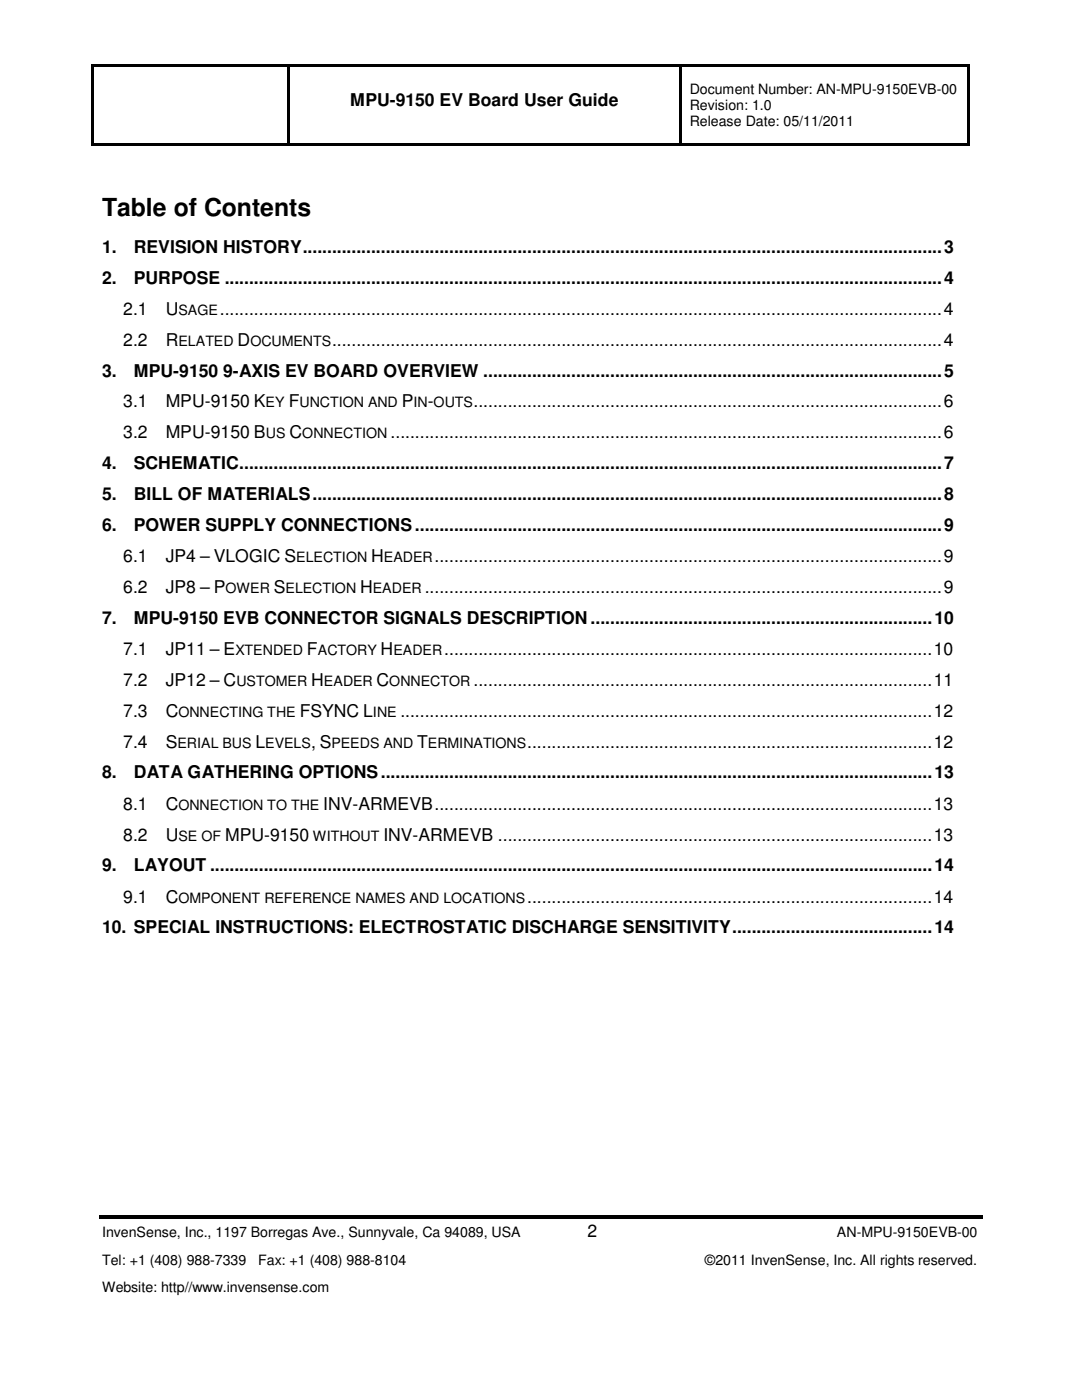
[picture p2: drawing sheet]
<svg xmlns="http://www.w3.org/2000/svg" width="216mm" height="279mm" viewBox="0 0 216 279" stroke-linecap="round" stroke-linejoin="round" font-family="sans-serif">
<defs><g id="words">
<text font-size="5" x="20.4" y="43.1">Table of Contents</text>
<g font-size="3.5">
<text x="69.9" y="21.1">MPU-9150 EV Board User Guide</text>
<text x="20.4" y="50.4">1.</text>
<text x="26.7" y="50.4">REVISION HISTORY ................................................................................................................................... 3</text>
<text x="20.4" y="56.6">2.</text>
<text x="26.7" y="56.6">PURPOSE ................................................................................................................................................... 4</text>
<text x="24.6" y="62.8">2.1</text>
<text x="33.1" y="62.8">U</text>
<text x="43.9" y="62.8">.................................................................................................................................................... 4</text>
<text x="24.6" y="69">2.2</text>
<text x="33.1" y="69">R</text>
<text x="47.4" y="69">D</text>
<text x="66.3" y="69">............................................................................................................................. 4</text>
<text x="20.4" y="75.1">3.</text>
<text x="26.7" y="75.1">MPU-9150 9-AXIS EV BOARD OVERVIEW .............................................................................................. 5</text>
<text x="24.6" y="81.3">3.1</text>
<text x="33.1" y="81.3">MPU-9150 K</text>
<text x="57.6" y="81.3">F</text>
<text x="80.2" y="81.3">P</text>
<text x="85.3" y="81.3">-</text>
<text x="94.5" y="81.3">................................................................................................ 6</text>
<text x="24.6" y="87.5">3.2</text>
<text x="33.1" y="87.5">MPU-9150 B</text>
<text x="57.8" y="87.5">C</text>
<text x="77.9" y="87.5">................................................................................................................. 6</text>
<text x="20.4" y="93.6">4.</text>
<text x="26.7" y="93.6">SCHEMATIC ................................................................................................................................................ 7</text>
<text x="20.4" y="99.8">5.</text>
<text x="26.7" y="99.8">BILL OF MATERIALS ................................................................................................................................. 8</text>
<text x="20.4" y="106">6.</text>
<text x="26.7" y="106">POWER SUPPLY CONNECTIONS ............................................................................................................ 9</text>
<text x="24.6" y="112.2">6.1</text>
<text x="33.1" y="112.2">JP4 – VLOGIC S</text>
<text x="74" y="112.2">H</text>
<text x="86.7" y="112.2">........................................................................................................ 9</text>
<text x="24.6" y="118.4">6.2</text>
<text x="33.1" y="118.4">JP8 – P</text>
<text x="54.7" y="118.4">S</text>
<text x="71.9" y="118.4">H</text>
<text x="84.8" y="118.4">.......................................................................................................... 9</text>
<text x="20.4" y="124.5">7.</text>
<text x="26.7" y="124.5">MPU-9150 EVB CONNECTOR SIGNALS DESCRIPTION ...................................................................... 10</text>
<text x="24.6" y="130.7">7.1</text>
<text x="33.1" y="130.7">JP11 – E</text>
<text x="61.3" y="130.7">F</text>
<text x="75.9" y="130.7">H</text>
<text x="88.6" y="130.7">....................................................................................................10</text>
<text x="24.6" y="136.9">7.2</text>
<text x="33.1" y="136.9">JP12 – C</text>
<text x="62.1" y="136.9">H</text>
<text x="75.1" y="136.9">C</text>
<text x="94.5" y="136.9">.............................................................................................. 11</text>
<text x="24.6" y="143.1">7.3</text>
<text x="33.1" y="143.1">C</text>
<text x="59.8" y="143.1">FSYNC L</text>
<text x="79.9" y="143.1">............................................................................................................. 12</text>
<text x="24.6" y="149.2">7.4</text>
<text x="33.1" y="149.2">S</text>
<text x="51" y="149.2">L</text>
<text x="62.1" y="149.2">, S</text>
<text x="83.2" y="149.2">T</text>
<text x="105.2" y="149.2">................................................................................... 12</text>
<text x="20.4" y="155.4">8.</text>
<text x="26.7" y="155.4">DATA GATHERING OPTIONS ................................................................................................................. 13</text>
<text x="24.6" y="161.6">8.1</text>
<text x="33.1" y="161.6">C</text>
<text x="64.5" y="161.6">INV-ARMEVB ...................................................................................................... 13</text>
<text x="24.6" y="167.8">8.2</text>
<text x="33.1" y="167.8">U</text>
<text x="44.9" y="167.8">MPU-9150</text>
<text x="76.5" y="167.8">INV-ARMEVB ......................................................................................... 13</text>
<text x="20.4" y="173.9">9.</text>
<text x="26.7" y="173.9">LAYOUT .................................................................................................................................................... 14</text>
<text x="24.6" y="180.1">9.1</text>
<text x="33.1" y="180.1">C</text>
<text x="105.2" y="180.1">................................................................................... 14</text>
<text x="20.4" y="186.2">10. SPECIAL INSTRUCTIONS: ELECTROSTATIC DISCHARGE SENSITIVITY ......................................... 14</text>
<text x="117.2" y="246.9">2</text>
</g>
<g font-size="2.8">
<text x="137.6" y="18.7">Document Number: AN-MPU-9150EVB-00</text>
<text x="137.6" y="21.9">Revision: 1.0</text>
<text x="137.6" y="25.1">Release Date: 05/11/2011</text>
<text x="35.6" y="62.8">SAGE</text>
<text x="35.6" y="69">ELATED</text>
<text x="50" y="69">OCUMENTS</text>
<text x="53" y="81.3">EY</text>
<text x="59.8" y="81.3">UNCTION AND</text>
<text x="82.5" y="81.3">IN OUTS</text>
<text x="53" y="87.5">US</text>
<text x="60.3" y="87.5">ONNECTION</text>
<text x="59.1" y="112.2">ELECTION</text>
<text x="76.6" y="112.2">EADER</text>
<text x="45" y="118.4">OWER</text>
<text x="57" y="118.4">ELECTION</text>
<text x="74.4" y="118.4">EADER</text>
<text x="47" y="130.7">XTENDED</text>
<text x="63.4" y="130.7">ACTORY</text>
<text x="78.5" y="130.7">EADER</text>
<text x="47.2" y="136.9">USTOMER</text>
<text x="64.6" y="136.9">EADER</text>
<text x="77.7" y="136.9">ONNECTOR</text>
<text x="35.6" y="143.1">ONNECTING THE</text>
<text x="74.4" y="143.1">INE</text>
<text x="35.4" y="149.2">ERIAL BUS</text>
<text x="52.9" y="149.2">EVELS</text>
<text x="66.1" y="149.2">PEEDS AND</text>
<text x="85.4" y="149.2">ERMINATIONS</text>
<text x="35.6" y="161.6">ONNECTION TO THE</text>
<text x="35.6" y="167.8">SE OF</text>
<text x="62.4" y="167.8">WITHOUT</text>
<text x="35.6" y="180.1">OMPONENT REFERENCE NAMES AND LOCATIONS</text>
<text x="20.4" y="246.9">InvenSense, Inc., 1197 Borregas Ave., Sunnyvale, Ca 94089, USA</text>
<text x="167" y="246.9">AN-MPU-9150EVB-00</text>
<text x="20.4" y="252.4">Tel: +1 (408) 988-7339</text>
<text x="20.4" y="257.8">Website: http//www.invensense.com</text>
<text x="51.5" y="252.4">Fax: +1 (408) 988-8104</text>
<text x="140.7" y="252.4">©2011 InvenSense, Inc. All rights reserved.</text>
</g>
</g></defs>
<g fill="#000">
<path d="M18.2 12.7h.5v.6h-.5zM18.7 12.7h38.7v.6h-38.7zM57.4 13.3h.5zM57.4 12.7h.5v.6h-.5zM57.9 12.7h77.6v.6h-77.6zM135.5 13.3h.5zM135.5 12.7h.5v.6h-.5zM136 12.7h57.1v.6h-57.1zM193.1 12.7h.5v.6h-.5zM18.2 13.3h.5v15.3h-.5zM18.2 28.6h.5v.5h-.5zM18.7 28.6h38.7v.5h-38.7z"/>
<path d="M57.4 13.3h.5v15.3h-.5zM57.4 28.6h.5v.5h-.5zM57.9 28.6h77.6v.5h-77.6zM135.5 13.3h.5v15.3h-.5zM135.5 28.6h.5v.5h-.5zM136 28.6h57.1v.5h-57.1zM193.1 13.3h.5v15.3h-.5zM193.1 28.6h.5v.5h-.5zM19.9 242.5h176.2v.8h-176.2z"/>
</g>
<use href="#words"/>
</svg>
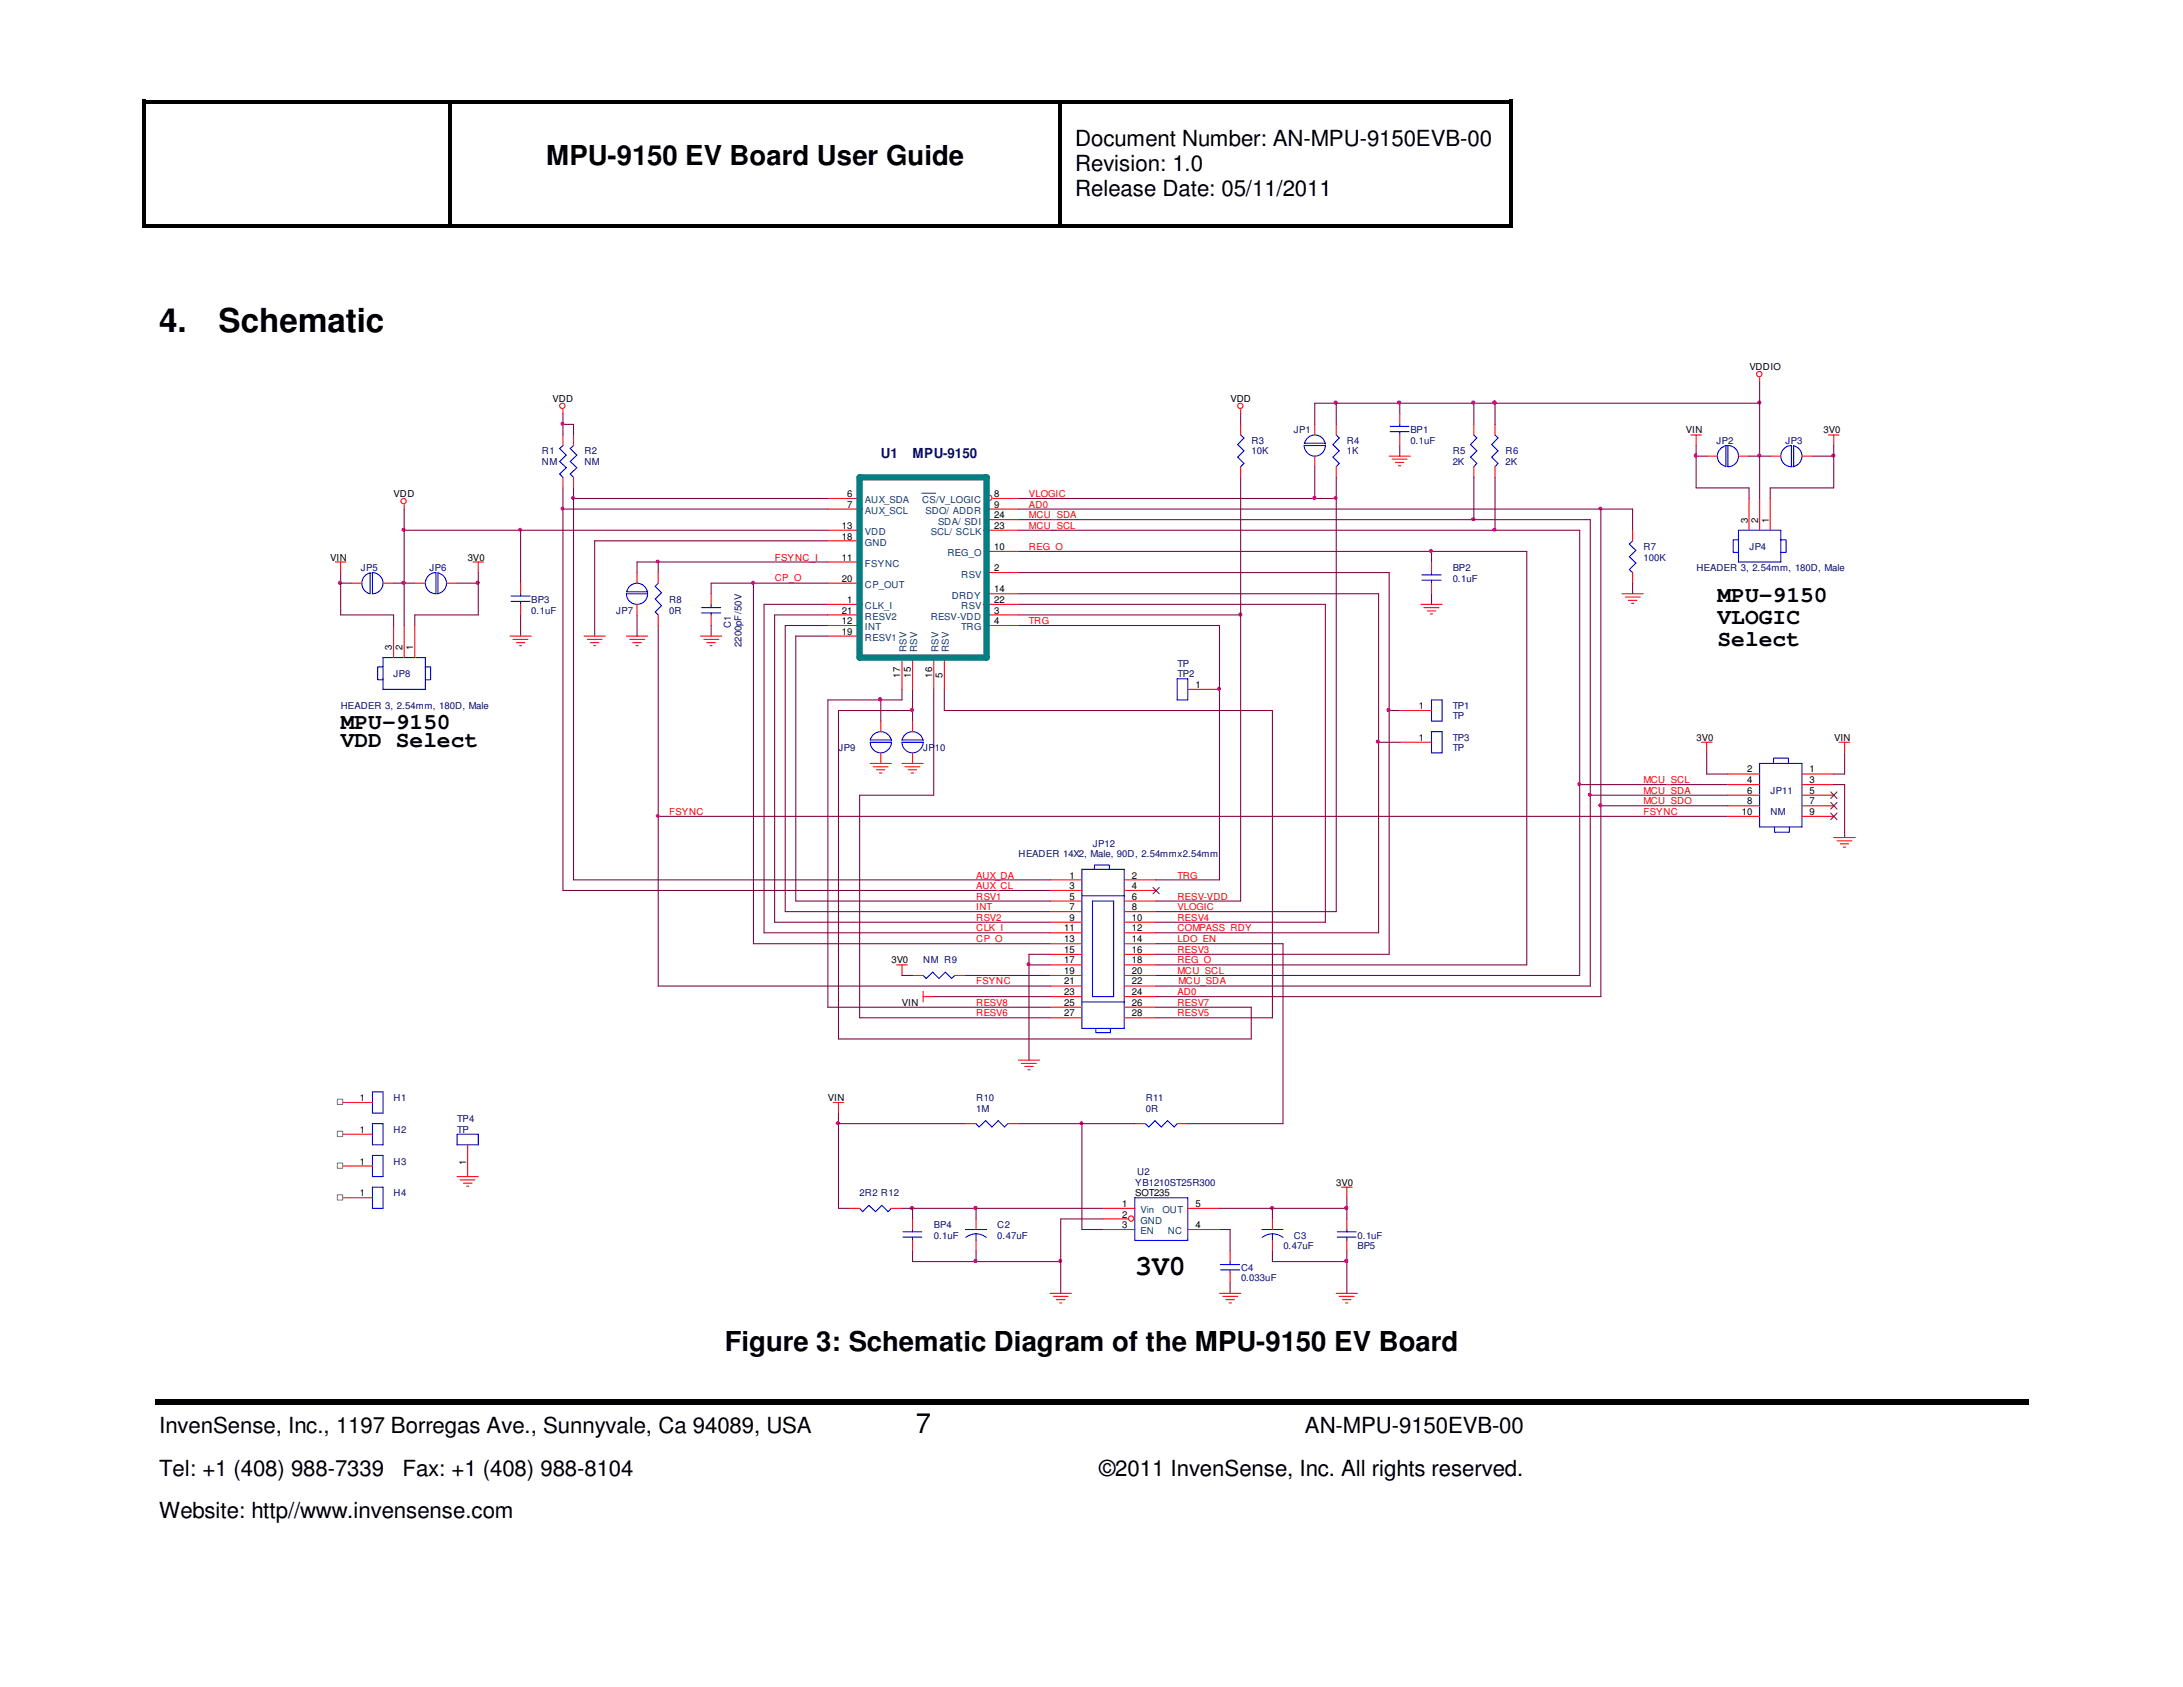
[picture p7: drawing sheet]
<svg xmlns="http://www.w3.org/2000/svg" width="279mm" height="216mm" viewBox="0 0 279 216" stroke-linecap="round" stroke-linejoin="round" font-family="sans-serif">
<defs><g id="words">
<g font-size="4.2">
<text x="20.4" y="42.5">4.</text>
<text x="28" y="42.5">Schematic</text>
</g>
<text font-size="3.7" x="145.3" y="163.2">3V0</text>
<g font-size="3.5">
<text x="69.9" y="21.1">MPU-9150 EV Board User Guide</text>
<text x="92.8" y="172.8">Figure 3: Schematic Diagram of the MPU-9150 EV Board</text>
<text x="117.2" y="183.4">7</text>
</g>
<g font-size="2.8">
<text x="137.6" y="18.7">Document Number: AN-MPU-9150EVB-00</text>
<text x="137.6" y="21.9">Revision: 1.0</text>
<text x="137.6" y="25.1">Release Date: 05/11/2011</text>
<text x="219.8" y="77">MPU-9150</text>
<text x="219.8" y="79.9">VLOGIC</text>
<text x="219.8" y="82.7">Select</text>
<text x="43.6" y="93.3">MPU-9150</text>
<text x="43.6" y="95.6">VDD Select</text>
<text x="20.4" y="183.4">InvenSense, Inc., 1197 Borregas Ave., Sunnyvale, Ca 94089, USA</text>
<text x="167" y="183.4">AN-MPU-9150EVB-00</text>
<text x="20.4" y="188.9">Tel: +1 (408) 988-7339</text>
<text x="51.5" y="188.9">Fax: +1 (408) 988-8104</text>
<text x="140.7" y="188.9">©2011 InvenSense, Inc. All rights reserved.</text>
<text x="20.4" y="194.3">Website: http//www.invensense.com</text>
</g>
<g font-size="1.8" fill="#000080">
<text x="112.7" y="58.7">U1</text>
<text x="116.8" y="58.7">MPU-9150</text>
</g>
<g font-size="1.2">
<text x="223.9" y="47.3">VDDIO</text>
<text x="70.7" y="51.4">VDD</text>
<text x="157.5" y="51.4">VDD</text>
<text x="215.8" y="55.5">VIN</text>
<text x="233.4" y="55.5">3V0</text>
<text x="50.4" y="63.6">VDD</text>
<text x="108.4" y="65">7</text>
<text x="108.4" y="63.6">6</text>
<text x="127.3" y="65">9</text>
<text x="127.3" y="63.6">8</text>
<text x="42.2" y="71.8">VIN</text>
<text x="59.9" y="71.8">3V0</text>
<text x="107.7" y="67.7">13</text>
<text x="107.7" y="69">18</text>
<text x="107.7" y="71.8">11</text>
<text x="127.3" y="66.3">24</text>
<text x="127.3" y="67.7">23</text>
<text x="127.3" y="70.4">10</text>
<text x="223.7" y="66.9" transform="rotate(-90 223.7 66.9)">3</text>
<text x="225" y="66.9" transform="rotate(-90 225 66.9)">2</text>
<text x="226.4" y="66.9" transform="rotate(-90 226.4 66.9)">1</text>
<text x="107.7" y="74.5">20</text>
<text x="108.4" y="77.2">1</text>
<text x="127.3" y="77.2">22</text>
<text x="127.3" y="73.1">2</text>
<text x="127.3" y="75.8">14</text>
<text x="50.2" y="83.2" transform="rotate(-90 50.2 83.2)">3</text>
<text x="51.5" y="83.2" transform="rotate(-90 51.5 83.2)">2</text>
<text x="52.9" y="83.2" transform="rotate(-90 52.9 83.2)">1</text>
<text x="107.7" y="79.9">12</text>
<text x="107.7" y="81.2">19</text>
<text x="107.7" y="78.5">21</text>
<text x="127.3" y="78.5">3</text>
<text x="127.3" y="79.9">4</text>
<text x="115.2" y="86.7" transform="rotate(-90 115.2 86.7)">17</text>
<text x="116.6" y="86.7" transform="rotate(-90 116.6 86.7)">15</text>
<text x="119.3" y="86.7" transform="rotate(-90 119.3 86.7)">16</text>
<text x="120.6" y="86.7" transform="rotate(-90 120.6 86.7)">5</text>
<text x="153" y="88">1</text>
<text x="181.6" y="90.7">1</text>
<text x="181.6" y="94.8">1</text>
<text x="217.1" y="94.8">3V0</text>
<text x="234.7" y="94.8">VIN</text>
<text x="223.6" y="98.8">2</text>
<text x="223.6" y="100.2">4</text>
<text x="223.6" y="101.6">6</text>
<text x="231.6" y="98.8">1</text>
<text x="231.6" y="100.2">3</text>
<text x="231.6" y="101.6">5</text>
<text x="222.9" y="104.3">10</text>
<text x="223.6" y="103">8</text>
<text x="231.6" y="103">7</text>
<text x="231.6" y="104.3">9</text>
<text x="136.9" y="112.4">1</text>
<text x="136.9" y="113.8">3</text>
<text x="144.9" y="112.4">2</text>
<text x="144.9" y="113.8">4</text>
<text x="136.2" y="119.2">11</text>
<text x="136.9" y="115.1">5</text>
<text x="136.9" y="116.5">7</text>
<text x="136.9" y="117.9">9</text>
<text x="144.9" y="115.1">6</text>
<text x="144.9" y="116.5">8</text>
<text x="144.9" y="117.9">10</text>
<text x="144.9" y="119.2">12</text>
<text x="114.1" y="123.3">3V0</text>
<text x="136.2" y="120.6">13</text>
<text x="136.2" y="121.9">15</text>
<text x="136.2" y="123.3">17</text>
<text x="136.2" y="124.6">19</text>
<text x="136.2" y="126">21</text>
<text x="144.9" y="120.6">14</text>
<text x="144.9" y="121.9">16</text>
<text x="144.9" y="123.3">18</text>
<text x="144.9" y="124.6">20</text>
<text x="144.9" y="126">22</text>
<text x="115.4" y="128.7">VIN</text>
<text x="136.2" y="127.3">23</text>
<text x="136.2" y="128.7">25</text>
<text x="136.2" y="130">27</text>
<text x="144.9" y="127.3">24</text>
<text x="144.9" y="128.7">26</text>
<text x="144.9" y="130">28</text>
<text x="46.1" y="140.9">1</text>
<text x="106" y="140.9">VIN</text>
<text x="46.1" y="149.1">1</text>
<text x="46.1" y="145">1</text>
<text x="59.6" y="149.1" transform="rotate(-90 59.6 149.1)">1</text>
<text x="46.1" y="153.1">1</text>
<text x="143.6" y="154.5">1</text>
<text x="143.6" y="155.8">2</text>
<text x="145.3" y="153.1">SOT235</text>
<text x="153" y="154.5">5</text>
<text x="171" y="151.8">3V0</text>
<text x="143.6" y="157.2">3</text>
<text x="153" y="157.2">4</text>
</g>
<g font-size="1.2" fill="#000080">
<text x="69.3" y="58.2">R1</text>
<text x="69.3" y="59.5">NM</text>
<text x="74.8" y="58.2">R2</text>
<text x="74.8" y="59.5">NM</text>
<text x="160.2" y="56.8">R3</text>
<text x="160.2" y="58.2">10K</text>
<text x="165.6" y="55.5">JP1</text>
<text x="172.4" y="56.8">R4</text>
<text x="172.4" y="58.2">1K</text>
<text x="180.5" y="55.5">BP1</text>
<text x="180.5" y="56.8">0.1uF</text>
<text x="185.9" y="58.2">R5</text>
<text x="185.9" y="59.5">2K</text>
<text x="192.7" y="58.2">R6</text>
<text x="192.7" y="59.5">2K</text>
<text x="219.7" y="56.8">JP2</text>
<text x="228.5" y="56.8">JP3</text>
<text x="210.4" y="70.4">R7</text>
<text x="210.4" y="71.8">100K</text>
<text x="223.9" y="70.4">JP4</text>
<text x="46.2" y="73.1">JP5</text>
<text x="55" y="73.1">JP6</text>
<text x="68" y="77.2">BP3</text>
<text x="85.6" y="77.2">R8</text>
<text x="185.9" y="73.1">BP2</text>
<text x="185.9" y="74.5">0.1uF</text>
<text x="217.1" y="73.1">HEADER 3, 2.54mm, 180D, Male</text>
<text x="68" y="78.5">0.1uF</text>
<text x="78.9" y="78.5">JP7</text>
<text x="85.6" y="78.5">0R</text>
<text x="93.6" y="80.3" transform="rotate(-90 93.6 80.3)">C1</text>
<text x="94.9" y="82.8" transform="rotate(-90 94.9 82.8)">2200pF/50V</text>
<text x="50.4" y="86.7">JP8</text>
<text x="150.7" y="86.7">TP2</text>
<text x="150.7" y="85.3">TP</text>
<text x="43.6" y="90.7">HEADER 3, 2.54mm, 180D, Male</text>
<text x="185.9" y="90.7">TP1</text>
<text x="185.9" y="92.1">TP</text>
<text x="185.9" y="94.8">TP3</text>
<text x="107.3" y="96.1">JP9</text>
<text x="118.2" y="96.1">JP10</text>
<text x="185.9" y="96.1">TP</text>
<text x="226.6" y="101.6">JP11</text>
<text x="226.6" y="104.3">NM</text>
<text x="130.3" y="109.7">HEADER 14X2, Male, 90D, 2.54mmx2.54mm</text>
<text x="139.9" y="108.4">JP12</text>
<text x="118.2" y="123.3">NM R9</text>
<text x="50.4" y="140.9">H1</text>
<text x="58.5" y="143.6">TP4</text>
<text x="124.9" y="140.9">R10</text>
<text x="124.9" y="142.3">1M</text>
<text x="146.6" y="140.9">R11</text>
<text x="146.6" y="142.3">0R</text>
<text x="50.4" y="149.1">H3</text>
<text x="50.4" y="145">H2</text>
<text x="58.5" y="145">TP</text>
<text x="50.4" y="153.1">H4</text>
<text x="110" y="153.1">2R2 R12</text>
<text x="145.3" y="151.8">YB1210ST25R300</text>
<text x="145.5" y="150.4">U2</text>
<text x="119.5" y="157.2">BP4</text>
<text x="119.5" y="158.5">0.1uF</text>
<text x="127.6" y="157.2">C2</text>
<text x="127.6" y="158.5">0.47uF</text>
<text x="164.3" y="159.9">0.47uF</text>
<text x="165.6" y="158.5">C3</text>
<text x="173.7" y="159.9">BP5</text>
<text x="173.7" y="158.5">0.1uF</text>
<text x="158.8" y="162.6">C4</text>
<text x="158.8" y="164">0.033uF</text>
</g>
<g font-size="1.2" fill="#004080">
<text x="110.7" y="65.8">AUX_SCL</text>
<text x="110.7" y="64.4">AUX_SDA</text>
<text x="118" y="64.4">CS/V_LOGIC</text>
<text x="118.4" y="65.8">SDO/ ADDR</text>
<text x="110.7" y="68.5">VDD</text>
<text x="110.7" y="69.8">GND</text>
<text x="119.1" y="68.5">SCL/ SCLK</text>
<text x="120.1" y="67.1">SDA/ SDI</text>
<text x="121.3" y="71.2">REG_O</text>
<text x="110.7" y="72.6">FSYNC</text>
<text x="110.7" y="75.3">CP_OUT</text>
<text x="110.7" y="78">CLK_I</text>
<text x="121.8" y="76.6">DRDY</text>
<text x="123" y="78">RSV</text>
<text x="123" y="73.9">RSV</text>
<text x="110.7" y="80.7">INT</text>
<text x="110.7" y="82">RESV1</text>
<text x="110.7" y="79.3">RESV2</text>
<text x="116" y="83.5" transform="rotate(-90 116 83.5)">RSV</text>
<text x="117.4" y="83.5" transform="rotate(-90 117.4 83.5)">RSV</text>
<text x="119.1" y="79.3">RESV-VDD</text>
<text x="120.1" y="83.5" transform="rotate(-90 120.1 83.5)">RSV</text>
<text x="121.5" y="83.5" transform="rotate(-90 121.5 83.5)">RSV</text>
<text x="123" y="80.7">TRG</text>
<text x="146" y="155.3">Vin</text>
<text x="148.8" y="155.3">OUT</text>
<text x="146" y="156.6">GND</text>
<text x="146" y="158">EN</text>
<text x="149.5" y="158">NC</text>
</g>
<g font-size="1.2" fill="#f00">
<text x="131.7" y="65">AD0</text>
<text x="131.7" y="63.6">VLOGIC</text>
<text x="99.2" y="71.8">FSYNC_I</text>
<text x="131.7" y="67.7">MCU_SCL</text>
<text x="131.7" y="70.4">REG_O</text>
<text x="131.7" y="66.3">MCU_SDA</text>
<text x="99.2" y="74.3">CP_O</text>
<text x="131.7" y="79.9">TRG</text>
<text x="210.4" y="100.2">MCU_SCL</text>
<text x="210.4" y="101.6">MCU_SDA</text>
<text x="85.6" y="104.3">FSYNC</text>
<text x="210.4" y="104.3">FSYNC</text>
<text x="210.4" y="103">MCU_SDO</text>
<text x="124.9" y="112.4">AUX_DA</text>
<text x="124.9" y="113.8">AUX_CL</text>
<text x="150.7" y="112.4">TRG</text>
<text x="124.9" y="116.5">INT</text>
<text x="124.9" y="117.9">RSV2</text>
<text x="124.9" y="115.1">RSV1</text>
<text x="124.9" y="119.2">CLK_I</text>
<text x="150.7" y="116.5">VLOGIC</text>
<text x="150.7" y="115.1">RESV-VDD</text>
<text x="150.7" y="119.2">COMPASS_RDY</text>
<text x="150.7" y="117.9">RESV4</text>
<text x="124.9" y="120.6">CP_O</text>
<text x="124.9" y="126">FSYNC</text>
<text x="150.7" y="124.6">MCU_SCL</text>
<text x="150.7" y="120.6">LDO_EN</text>
<text x="150.7" y="121.9">RESV3</text>
<text x="150.7" y="123.3">REG_O</text>
<text x="150.8" y="126">MCU_SDA</text>
<text x="124.9" y="130">RESV6</text>
<text x="124.9" y="128.7">RESV8</text>
<text x="150.7" y="130">RESV5</text>
<text x="150.7" y="127.3">AD0</text>
<text x="150.7" y="128.7">RESV7</text>
</g>
</g></defs>
<g fill="#000">
<path d="M18.2 12.7h.5v.6h-.5zM18.2 12.7h.5v.5h-.5zM18.2 13.3h.5v15.3h-.5zM18.7 12.7h38.7v.5h-38.7zM57.4 13.3h.5zM57.4 12.7h.5v.5h-.5zM57.4 13.3h.5v15.3h-.5zM57.9 12.7h77.6v.5h-77.6zM135.5 13.3h.5zM135.5 12.7h.5v.5h-.5zM135.5 13.3h.5v15.3h-.5zM136 12.7h57.1v.5h-57.1z"/>
<path d="M193.1 12.7h.5v.6h-.5zM193.1 12.7h.5v.5h-.5zM193.1 13.3h.5v15.3h-.5zM18.2 28.6h.5v.5h-.5zM18.7 28.6h38.7v.5h-38.7zM57.4 28.6h.5v.5h-.5zM57.9 28.6h77.6v.5h-77.6zM135.5 28.6h.5v.5h-.5zM136 28.6h57.1v.5h-57.1zM193.1 28.6h.5v.5h-.5zM19.9 179h239.7v.8h-239.7z"/>
</g>
<path d="M148 123.5h47.4M116.8 154.6h8.1" fill="none" stroke="#800040" stroke-width=".14"/>
<path d="M58.5 150.6h2.7M58.9 151h1.9M59.3 151.4h1.1M59.7 151.8h.3" fill="none" stroke="#f00" stroke-width=".14"/>
<path d="M116.6 154.4h.3v.3l-.2 .1-.1-.1z" fill-rule="evenodd" fill="#f0f"/>
<path d="M116.6 154.4h.3v.3l-.2 .1-.1-.1z" fill="none" stroke="#f0f" stroke-width=".14"/>
<path d="M124.7 154.4h.3v.3l-.2 .1-.1-.1-.1-.1z" fill-rule="evenodd" fill="#f0f"/>
<path d="M124.7 154.4h.3v.3l-.2 .1-.1-.1-.1-.1z" fill="none" stroke="#f0f" stroke-width=".14"/>
<path d="M130.3 66.5h58.3" fill="none" stroke="#800040" stroke-width=".14"/>
<path d="M188.4 66.3h.3v.3h-.3z" fill-rule="evenodd" fill="#f0f"/>
<path d="M188.4 66.3h.3v.3h-.3z" fill="none" stroke="#f0f" stroke-width=".14"/>
<path d="M188.6 51.6h-9.4v1.4M43.6 78.7h6.8M84.2 104.5h136.9M203.5 101.8h17.6M110 130.3h24.4" fill="none" stroke="#800040" stroke-width=".14"/>
<path d="M188.6 55.7l.4 .3-.8 .9 .8 .8-.8 .8 .8 .8-.4 .4M47.7 151.9h1.3v2.7h-1.3z" fill="none" stroke="#00f" stroke-width=".14"/>
<path d="M188.6 54.3v1.4M188.6 59.7v1.4M43.6 153.3h4.1" fill="none" stroke="#f00" stroke-width=".14"/>
<path d="M43.2 152.9h.7v.7h-.7z" fill-rule="evenodd" fill="#fff"/>
<path d="M43.2 152.9h.7v.7h-.7z" fill="none" stroke="#808080" stroke-width=".14"/>
<path d="M131.7 123.5v12.2" fill="none" stroke="#800040" stroke-width=".14"/>
<path d="M131.5 123.2h.3v.4h-.3z" fill-rule="evenodd" fill="#f0f"/>
<path d="M131.5 123.2h.3v.4h-.3z" fill="none" stroke="#f0f" stroke-width=".14"/>
<path d="M72.1 65.2v48.8M107.3 154.6h1.4M152 143.8h12.2M162.9 160.1v1.4" fill="none" stroke="#800040" stroke-width=".14"/>
<path d="M191.3 55.7l.4 .3-.8 .9 .8 .8-.8 .8 .8 .8-.4 .4M228.2 57.6l.7-.5 .4-.1v2.7a1.35 1.35 0 0 1-1.2-.7 1.35 1.35 0 0 1 .1-1.4zM229.6 57.1a1.36 1.36 0 0 1 1 1.4 1.36 1.36 0 0 1-1.2 1.2M229.6 57v2.7" fill="none" stroke="#00f" stroke-width=".14"/>
<path d="M191.3 54.3v1.4M191.3 59.7v1.4M226.6 58.4h1.3M230.6 58.4h1.4M80.2 81.4h2.7M80.6 81.8h1.9M81 82.3h1.1M81.4 82.6h.3" fill="none" stroke="#f00" stroke-width=".14"/>
<path d="M71.9 64.9h.2v.3h-.2z" fill-rule="evenodd" fill="#f0f"/>
<path d="M71.9 64.9h.2v.3h-.2z" fill="none" stroke="#f0f" stroke-width=".14"/>
<g fill="none" stroke="#800040" stroke-width=".14">
<path d="M73.4 54.3v1.4M217.1 58.4h1.3M51.7 74.6h1.4M58.5 74.6h2.7M66.6 78.7v2.7M97.8 77.3h8.2M130.3 73.3h47.5M188.6 61.1v5.4M223.9 62.4v1.4M84.2 80.1v24.4M119.5 127.5h14.9M116.8 154.6v1.4"/>
<path d="M124.9 160.1v1.4M172.4 161.5v4"/>
</g>
<path d="M207.6 76h2.7M208 76.4h1.9M208.4 76.8h1.1M208.8 77.2h.3" fill="none" stroke="#f00" stroke-width=".14"/>
<path d="M61 74.4h.3v.3l-.2 .1-.1-.1-.1-.1z" fill-rule="evenodd" fill="#f0f"/>
<path d="M61 74.4h.3v.3l-.2 .1-.1-.1-.1-.1z" fill="none" stroke="#f0f" stroke-width=".14"/>
<path d="M158.8 53v1.3M168.3 59.7v4.1M188.6 51.6v2.7M217.1 58.4v4h6.8M130.3 76h46.1M116.8 88.2v2.7M119.5 88.2v13.6M177.8 90.9h1.4M72.1 114h62.3M202.2 100.4h18.9M124.9 154.6v1.4" fill="none" stroke="#800040" stroke-width=".14"/>
<path d="M171 54.3v1.4M171 59.7v1.4M234 55.7h1.4M234.7 55.7v1.3M43.6 149.2h4.1M156.1 165.5h2.7M156.5 165.9h1.9M156.9 166.3h1.1M157.3 166.8h.3" fill="none" stroke="#f00" stroke-width=".14"/>
<path d="M171 55.7l.4 .3-.8 .9 .8 .8-.8 .8 .8 .8-.4 .4M47.7 147.9h1.3v2.7h-1.3z" fill="none" stroke="#00f" stroke-width=".14"/>
<path d="M43.2 148.8h.7v.7h-.7z" fill-rule="evenodd" fill="#fff"/>
<path d="M43.2 148.8h.7v.7h-.7z" fill="none" stroke="#808080" stroke-width=".14"/>
<path d="M146.6 143.8l.4 .4 .8-.8 .8 .8 .8-.8 .9 .8 .4-.4" fill="none" stroke="#00f" stroke-width=".14"/>
<path d="M145.2 143.8h1.4M150.7 143.8h1.3" fill="none" stroke="#f00" stroke-width=".14"/>
<path d="M51.7 67.9h14.9" fill="none" stroke="#800040" stroke-width=".14"/>
<path d="M51.5 67.7h.3v.2h-.3z" fill-rule="evenodd" fill="#f0f"/>
<path d="M51.5 67.7h.3v.2h-.3z" fill="none" stroke="#f0f" stroke-width=".14"/>
<path d="M66.4 67.7h.3v.2h-.3z" fill-rule="evenodd" fill="#f0f"/>
<path d="M66.4 67.7h.3v.2h-.3z" fill="none" stroke="#f0f" stroke-width=".14"/>
<path d="M76.1 69.2v12.2M84.2 71.9v1.4M183.2 70.6h12.2M100.5 80.1h5.5M107.3 133h52.8" fill="none" stroke="#800040" stroke-width=".14"/>
<path d="M84 71.7h.3v.3h-.3z" fill-rule="evenodd" fill="#f0f"/>
<path d="M84 71.7h.3v.3h-.3z" fill="none" stroke="#f0f" stroke-width=".14"/>
<path d="M217.1 57v1.4" fill="none" stroke="#800040" stroke-width=".14"/>
<path d="M216.9 58.2l.1-.1 .2 .1v.2h-.3z" fill-rule="evenodd" fill="#f0f"/>
<path d="M216.9 58.2l.1-.1 .2 .1v.2h-.3z" fill="none" stroke="#f0f" stroke-width=".14"/>
<path d="M53.1 78.7v1.4M202.2 67.9v32.5" fill="none" stroke="#800040" stroke-width=".14"/>
<g fill="none" stroke="#f00" stroke-width=".14">
<path d="M51.7 64.6v.6M124.9 156v1.4M124.9 158.7v1.4"/>
<circle cx="51.7" cy="64.1" r=".33"/>
</g>
<path d="M123.6 157.4h2.7M124.9 157.9a2.16 2.16 0 0 1 1.3 .5M124.9 157.9a2.16 2.16 0 0 0-1.3 .5M124.9 157.9v.8" fill="none" stroke="#00f" stroke-width=".14"/>
<path d="M202 100.2h.3v.3h-.3z" fill-rule="evenodd" fill="#f0f"/>
<path d="M202 100.2h.3v.3h-.3z" fill="none" stroke="#f0f" stroke-width=".14"/>
<path d="M76.1 69.2h29.9M130.3 65.2h74.6M106 89.6v39.3M176.4 95h2.8" fill="none" stroke="#800040" stroke-width=".14"/>
<path d="M216.4 55.7h1.4M217.1 55.7v1.3M179.2 90.9h4" fill="none" stroke="#f00" stroke-width=".14"/>
<path d="M183.2 89.6h1.4v2.7h-1.4z" fill="none" stroke="#00f" stroke-width=".14"/>
<path d="M204.7 64.9h.3v.3h-.3z" fill-rule="evenodd" fill="#f0f"/>
<path d="M204.7 64.9h.3v.3h-.3z" fill="none" stroke="#f0f" stroke-width=".14"/>
<path d="M232 58.4h2.7M100.5 80.1v36.6" fill="none" stroke="#800040" stroke-width=".14"/>
<circle cx="234.7" cy="58.3" r=".21" fill="#f0f"/>
<circle cx="234.7" cy="58.3" r=".21" fill="none" stroke="#f0f" stroke-width=".14"/>
<path d="M191.3 51.6h33.9" fill="none" stroke="#800040" stroke-width=".14"/>
<circle cx="225.2" cy="51.5" r=".21" fill="#f0f"/>
<circle cx="225.2" cy="51.5" r=".21" fill="none" stroke="#f0f" stroke-width=".14"/>
<path d="M191.1 51.4h.3v.3h-.3v-.2z" fill-rule="evenodd" fill="#f0f"/>
<path d="M191.1 51.4h.3v.3h-.3v-.2z" fill="none" stroke="#f0f" stroke-width=".14"/>
<path d="M112.7 89.6v2.7" fill="none" stroke="#800040" stroke-width=".14"/>
<circle cx="112.6" cy="89.5" r=".21" fill="#f0f"/>
<circle cx="112.6" cy="89.5" r=".21" fill="none" stroke="#f0f" stroke-width=".14"/>
<path d="M81.5 78.7v2.7M91 74.6v1.4M130.3 67.9h61M183.2 70.6v1.3M218.4 96.3v2.8M110 101.8v28.5M131.7 122.1v1.4" fill="none" stroke="#800040" stroke-width=".14"/>
<path d="M49 85.3h-.7v1.7h.7v-.1M49 84.2h5.4v4h-5.4zM54.4 85.5v-.2h.7v1.7h-.7M150.7 86.9h1.3v2.7h-1.3zM225.2 97.7h5.4v8.1h-5.4zM227 97.7v-.7h1.9v.7M227.1 105.8v.7h1.9v-.7" fill="none" stroke="#00f" stroke-width=".14"/>
<g fill="none" stroke="#f00" stroke-width=".14">
<path d="M50.4 80.1v4.1M51.7 80.1v4.1M53.1 80.1v4.1M152 88.2h4.1M221.1 99.1h4.1M230.6 99.1h4.1M221.1 100.4h4.1M221.1 101.8h4.1M221.1 103.1h4.1M221.1 104.5h4.1M230.6 100.4h4.1M230.6 101.8h4.1"/>
<path d="M230.6 103.1h4.1M230.6 104.5h4.1"/>
</g>
<path d="M234.3 101.3l.8 .9M234.3 102.7l.8 .8M234.3 104.1l.8 .8M235.1 101.3l-.8 .9M235.1 102.7l-.8 .8M235.1 104.1l-.8 .8" fill="none" stroke="#804000" stroke-width=".14"/>
<path d="M191.1 67.7h.3v.2h-.3v-.1z" fill-rule="evenodd" fill="#f0f"/>
<path d="M191.1 67.7h.3v.2h-.3v-.1z" fill="none" stroke="#f0f" stroke-width=".14"/>
<path d="M51.7 74.6v5.5M96.4 74.6h9.6M97.8 77.3v42.1h36.6M130.3 77.3h39.3M171 61.1v2.7M116.8 90.9v1.4M218.4 99.1h2.7M84.2 104.5v21.7M204.9 103.1h16.2M131.7 122.1h2.7M148 126.2h55.5" fill="none" stroke="#800040" stroke-width=".14"/>
<path d="M166.9 57h2.7a1.35 1.35 0 0 1-1.3 1.4 1.35 1.35 0 0 1-1.4-1.4zM166.9 56.7h2.7M167 56.8a1.35 1.35 0 0 1 1.3-1.1 1.35 1.35 0 0 1 1.3 1.2M138.5 111.3h5.4v20.3h-5.4zM138.5 114.6h5.4M139.8 115.3h2.7v12.2h-2.7zM140.1 111.3v-.6h1.9v.6M138.5 128.2h5.4M140.3 131.6v.6h1.8v-.6M58.5 145.2h2.7v1.3h-2.7z" fill="none" stroke="#00f" stroke-width=".14"/>
<g fill="none" stroke="#f00" stroke-width=".14">
<path d="M168.3 54.3v1.4M168.3 58.4v1.3M111.4 97.7h2.7M111.8 98.1h1.9M112.2 98.5h1M112.6 98.9h.3M134.4 112.6h4.1M134.4 114h4.1M134.4 115.3h4.1M134.4 116.7h4.1M134.4 118h4.1M134.4 119.4h4.1"/>
<path d="M143.9 112.6h4.1M143.9 114h4.1M143.9 115.3h4.1M143.9 116.7h4.1M143.9 118h4.1M143.9 119.4h4.1M134.4 120.8h4.1M134.4 122.1h4.1M134.4 123.5h4.1M134.4 124.8h4.1M134.4 126.2h4.1M134.4 127.5h4.1"/>
<path d="M134.4 128.9h4.1M134.4 130.3h4.1M143.9 120.8h4.1M143.9 122.1h4.1M143.9 123.5h4.1M143.9 124.8h4.1M143.9 126.2h4.1M143.9 127.5h4.1M143.9 128.9h4.1M143.9 130.3h4.1M59.9 146.5v4.1"/>
</g>
<path d="M147.6 113.6l.8 .8M148.4 113.6l-.8 .8" fill="none" stroke="#804000" stroke-width=".14"/>
<path d="M84 104.3h.3v.2h-.3z" fill-rule="evenodd" fill="#f0f"/>
<path d="M84 104.3h.3v.2h-.3z" fill="none" stroke="#f0f" stroke-width=".14"/>
<path d="M130.3 78.7h28.5" fill="none" stroke="#800040" stroke-width=".14"/>
<path d="M158.6 78.5h.3l.1 .2-.1 .1-.2 .1-.1-.1z" fill-rule="evenodd" fill="#f0f"/>
<path d="M158.6 78.5h.3l.1 .2-.1 .1-.2 .1-.1-.1z" fill="none" stroke="#f0f" stroke-width=".14"/>
<path d="M43.6 73.3v1.3M53.1 78.7h8.1M72.1 65.2h33.9M209 65.2v2.7M176.4 95v24.4M148 128.9h12.1M172.4 160.1v1.4" fill="none" stroke="#800040" stroke-width=".14"/>
<path d="M81.5 73.3v1.3M81.5 77.3v1.4M181.9 77.3h2.7M182.2 77.8h1.9M182.7 78.2h1.1M183 78.6h.3M171.7 151.9h1.4M172.4 151.9v1.4M171 165.5h2.7M171.4 165.9h1.9M171.8 166.3h1.1M172.2 166.8h.3" fill="none" stroke="#f00" stroke-width=".14"/>
<path d="M80.2 76h2.7a1.35 1.35 0 0 1-1.4 1.3 1.35 1.35 0 0 1-1.3-1.3zM80.2 75.7h2.7M80.2 75.7a1.35 1.35 0 0 1 1.4-1.1 1.35 1.35 0 0 1 1.3 1.3" fill="none" stroke="#00f" stroke-width=".14"/>
<path d="M43.4 74.4h.3v.3l-.2 .1-.1-.1z" fill-rule="evenodd" fill="#f0f"/>
<path d="M43.4 74.4h.3v.3l-.2 .1-.1-.1z" fill="none" stroke="#f0f" stroke-width=".14"/>
<path d="M130.3 70.6h52.9" fill="none" stroke="#800040" stroke-width=".14"/>
<path d="M183 70.4h.3v.2h-.3z" fill-rule="evenodd" fill="#f0f"/>
<path d="M183 70.4h.3v.2h-.3z" fill="none" stroke="#f0f" stroke-width=".14"/>
<path d="M51.7 67.9v6.7M115.4 154.6h1.4M135.8 156h5.4" fill="none" stroke="#800040" stroke-width=".14"/>
<path d="M51.5 74.4h.3v.3l-.2 .1-.1-.1z" fill-rule="evenodd" fill="#f0f"/>
<path d="M51.5 74.4h.3v.3l-.2 .1-.1-.1z" fill="none" stroke="#f0f" stroke-width=".14"/>
<path d="M130.3 63.8h38M226.6 62.4v1.4M115.4 88.2v1.4" fill="none" stroke="#800040" stroke-width=".14"/>
<g fill="none" stroke="#f00" stroke-width=".14">
<path d="M72.1 52.4v.6M43.6 145.2h4.1"/>
<circle cx="72" cy="51.9" r=".34"/>
</g>
<path d="M47.7 143.8h1.3v2.7h-1.3z" fill="none" stroke="#00f" stroke-width=".14"/>
<path d="M43.2 144.8h.7v.7h-.7z" fill-rule="evenodd" fill="#fff"/>
<path d="M43.2 144.8h.7v.7h-.7z" fill="none" stroke="#808080" stroke-width=".14"/>
<path d="M47.4 73.3v2.7a1.36 1.36 0 0 1-1.1-1.4 1.36 1.36 0 0 1 1.2-1.3M47.7 73.3a1.35 1.35 0 0 1 1.3 1.3 1.35 1.35 0 0 1-1.3 1.4zM209 69.2l-.5 .4 .9 .8-.9 .8 .9 .9-.9 .8 .5 .4" fill="none" stroke="#00f" stroke-width=".14"/>
<g fill="none" stroke="#f00" stroke-width=".14">
<path d="M177.8 58.4h2.7M178.2 58.8h1.9M178.6 59.2h1.1M179 59.6h.3M45 74.6h1.3M49 74.6h1.4M209 67.9v1.3M209 73.3v1.3M114.8 123.5h1.3M115.4 123.5v1.3M134.4 165.5h2.7M134.8 165.9h1.9"/>
<path d="M135.2 166.3h1.1M135.6 166.8h.3"/>
</g>
<path d="M234.7 57v1.4M50.4 78.7v1.4M66.6 67.9h39.4M72.1 62.4v2.8M110 101.8h9.5M138.5 143.8v13.6" fill="none" stroke="#800040" stroke-width=".14"/>
<path d="M138.3 143.6h.2v.3h-.2z" fill-rule="evenodd" fill="#f0f"/>
<path d="M138.3 143.6h.2v.3h-.2z" fill="none" stroke="#f0f" stroke-width=".14"/>
<path d="M73.4 62.4v1.4M156.1 88.2v24.4M148 127.5h56.9" fill="none" stroke="#800040" stroke-width=".14"/>
<path d="M220.9 57v2.7M221 57a1.35 1.35 0 0 0-1.2 1.3 1.35 1.35 0 0 0 1.1 1.4M221.1 57a1.35 1.35 0 0 1 1.4 1.4 1.35 1.35 0 0 1-1.4 1.3z" fill="none" stroke="#00f" stroke-width=".14"/>
<path d="M218.4 58.4h1.4M222.5 58.4h1.4" fill="none" stroke="#f00" stroke-width=".14"/>
<path d="M155.9 88h.3v.3h-.3z" fill-rule="evenodd" fill="#f0f"/>
<path d="M155.9 88h.3v.3h-.3z" fill="none" stroke="#f0f" stroke-width=".14"/>
<path d="M191.3 51.6v2.7M225.2 51.6v6.8" fill="none" stroke="#800040" stroke-width=".14"/>
<circle cx="225.2" cy="58.3" r=".21" fill="#f0f"/>
<circle cx="225.2" cy="58.3" r=".21" fill="none" stroke="#f0f" stroke-width=".14"/>
<path d="M168.3 51.6v2.7M225.2 58.4h1.4M61.2 74.6v4.1M148 116.7h23M156.1 157.4h1.3M162.9 154.6h9.5" fill="none" stroke="#800040" stroke-width=".14"/>
<path d="M162.7 154.4h.3v.2v.1l-.2 .1-.1-.1z" fill-rule="evenodd" fill="#f0f"/>
<path d="M162.7 154.4h.3v.2v.1l-.2 .1-.1-.1z" fill="none" stroke="#f0f" stroke-width=".14"/>
<path d="M172.1 154.4h.4v.3l-.2 .1-.2-.1z" fill-rule="evenodd" fill="#f0f"/>
<path d="M172.1 154.4h.3v.3l-.1 .1-.2-.1z" fill="none" stroke="#f0f" stroke-width=".14"/>
<path d="M73.4 63.8h32.6" fill="none" stroke="#800040" stroke-width=".14"/>
<path d="M73.2 63.6h.3v.3h-.3z" fill-rule="evenodd" fill="#f0f"/>
<path d="M73.2 63.6h.3v.3h-.3z" fill="none" stroke="#f0f" stroke-width=".14"/>
<path d="M73.4 63.8v48.8M84.2 71.9h21.8M188.6 66.5h14.9M204.9 65.2h4.1M101.9 115.3h32.5M96.4 120.8h38M116.8 161.5h19" fill="none" stroke="#800040" stroke-width=".14"/>
<path d="M115.4 97.7h2.8M115.8 98.1h1.9M116.2 98.5h1.1M116.6 98.9h.3" fill="none" stroke="#f00" stroke-width=".14"/>
<path d="M124.7 161.2h.3v.3h-.3l-.1-.1z" fill-rule="evenodd" fill="#f0f"/>
<path d="M124.7 161.2h.3v.3h-.3l-.1-.1z" fill="none" stroke="#f0f" stroke-width=".14"/>
<path d="M135.6 161.2h.2v.3h-.2z" fill-rule="evenodd" fill="#f0f"/>
<path d="M135.6 161.2h.2v.3h-.2z" fill="none" stroke="#f0f" stroke-width=".14"/>
<path d="M168.3 51.6h2.7M223.9 58.4h1.3M51.7 65.2v2.7M81.5 71.9h2.7M91 74.6h5.4M131.7 123.5h2.7" fill="none" stroke="#800040" stroke-width=".14"/>
<path d="M73.4 57l-.4 .4 .8 .9-.8 .8 .8 .8-.8 .8 .4 .4M89.8 77.8h2.4M89.8 78.4h2.4M91 77.3v.5M91 78.4v.3" fill="none" stroke="#00f" stroke-width=".14"/>
<path d="M73.4 55.7v1.3M73.4 61.1v1.3M91 76v1.3M91 78.7v1.4" fill="none" stroke="#f00" stroke-width=".14"/>
<circle cx="170.9" cy="51.5" r=".21" fill="#f0f"/>
<circle cx="170.9" cy="51.5" r=".21" fill="none" stroke="#f0f" stroke-width=".14"/>
<path d="M179.2 57v1.4M96.4 74.6v46.2M209 74.6v1.4M130.3 80.1h25.8M236.1 100.4v6.8M148 130.3h14.9" fill="none" stroke="#800040" stroke-width=".14"/>
<path d="M72.1 57l-.5 .4 .9 .9-.9 .8 .9 .8-.9 .8 .5 .4M118.2 124.8l.3 .4 .9-.8 .8 .8 .8-.8 .8 .8 .4-.4" fill="none" stroke="#00f" stroke-width=".14"/>
<path d="M72.1 55.7v1.3M72.1 61.1v1.3M116.8 124.8h1.4M122.2 124.8h1.4" fill="none" stroke="#f00" stroke-width=".14"/>
<path d="M96.2 74.4h.3l.1 .2-.1 .1-.1 .1-.2-.1z" fill-rule="evenodd" fill="#f0f"/>
<path d="M96.2 74.4h.3l.1 .2-.1 .1-.1 .1-.2-.1z" fill="none" stroke="#f0f" stroke-width=".14"/>
<path d="M204.9 65.2v37.9M120.9 88.2v2.7M148 115.3h10.8" fill="none" stroke="#800040" stroke-width=".14"/>
<path d="M115.4 95h2.8a1.35 1.35 0 0 1-1.4 1.3 1.35 1.35 0 0 1-1.4-1.3zM115.4 94.7a1.38 1.38 0 0 1 1.4-1.1 1.38 1.38 0 0 1 1.4 1.2M115.4 94.7h2.8" fill="none" stroke="#00f" stroke-width=".14"/>
<path d="M116.8 92.3v1.3M116.8 96.3v1.4" fill="none" stroke="#f00" stroke-width=".14"/>
<path d="M204.7 102.9h.3v.3h-.3z" fill-rule="evenodd" fill="#f0f"/>
<path d="M204.7 102.9h.3v.3h-.3z" fill="none" stroke="#f0f" stroke-width=".14"/>
<path d="M43.6 74.6v4.1M158.8 61.1v17.6M168.3 63.8h2.7M91 80.1v1.3M177.8 90.9v31.2M138.5 157.4h2.7" fill="none" stroke="#800040" stroke-width=".14"/>
<path d="M55 73.5l.4-.1 .4-.1v2.7a1.35 1.35 0 0 1-1.3-.9 1.35 1.35 0 0 1 .5-1.6zM56 73.3a1.35 1.35 0 0 1 1.1 1.4 1.35 1.35 0 0 1-1.2 1.3M56 73.3v2.7M84.2 74.6l-.3 .5 .8 .8-.8 .8 .8 .8-.8 .8 .3 .4M171.2 158.3h2.4M171.2 157.6h2.4M172.4 157.4v.2M172.4 158.3v.4" fill="none" stroke="#00f" stroke-width=".14"/>
<path d="M53.1 74.6h1.3M57.1 74.6h1.4M84.2 73.3v1.3M84.2 78.7v1.4M172.4 156v1.4M172.4 158.7v1.4" fill="none" stroke="#f00" stroke-width=".14"/>
<path d="M168.1 63.6h.3v.3h-.3z" fill-rule="evenodd" fill="#f0f"/>
<path d="M168.1 63.6h.3v.3h-.3z" fill="none" stroke="#f0f" stroke-width=".14"/>
<path d="M170.8 63.6h.3v.3h-.3z" fill-rule="evenodd" fill="#f0f"/>
<path d="M170.8 63.6h.3v.3h-.3z" fill="none" stroke="#f0f" stroke-width=".14"/>
<path d="M171 51.6v2.7M171 63.8v52.9M120.9 90.9h42M160.1 128.9v4.1M157.4 164.2v1.3M162.9 161.5h9.5" fill="none" stroke="#800040" stroke-width=".14"/>
<path d="M156.2 161.8h2.5M156.2 162.5h2.5M157.4 161.5v.3M157.4 162.5v.3" fill="none" stroke="#00f" stroke-width=".14"/>
<path d="M157.4 160.1v1.4M157.4 162.8v1.4" fill="none" stroke="#f00" stroke-width=".14"/>
<circle cx="172.3" cy="161.4" r=".21" fill="#f0f"/>
<circle cx="172.3" cy="161.4" r=".21" fill="none" stroke="#f0f" stroke-width=".14"/>
<path d="M235.4 95h1.4M236.1 95v1.3M43.6 141.1h4.1" fill="none" stroke="#f00" stroke-width=".14"/>
<path d="M106 128.9h28.4" fill="none" stroke="#800040" stroke-width=".14"/>
<path d="M47.7 139.7h1.3v2.8h-1.3z" fill="none" stroke="#00f" stroke-width=".14"/>
<path d="M43.2 140.7h.7v.7h-.7z" fill-rule="evenodd" fill="#fff"/>
<path d="M43.2 140.7h.7v.7h-.7z" fill="none" stroke="#808080" stroke-width=".14"/>
<path d="M110 61.1h16.3v23.1h-16.3z" fill="none" stroke="#00f" stroke-width=".14"/>
<path d="M106 74.6h4M106 77.3h4M110 77l.4 .3-.4 .5M126.3 66.5h4M126.3 65.2h4" fill="none" stroke="#f00" stroke-width=".14"/>
<circle cx="126.6" cy="63.7" r=".34" fill="#fff"/>
<g fill="none" stroke="#f00" stroke-width=".14">
<path d="M106 63.8h4M106 67.9h4M106 69.2h4M106 71.9h4M106 65.2h4M106 78.7h4M110 64.7l.4 .5-.4 .4M126.3 67.9h4M126.3 67.5l-.4 .4 .4 .4M126.3 70.6h4M126.3 77l-.4 .3 .4 .5M126.3 77.3h4"/>
<path d="M126.3 73.3h4M126.3 78.7h4M126.3 76h4M127.1 63.8h3.2M106 80.1h4M106 81.4h4M115.4 84.2v4M116.8 84.2v4M119.5 84.2v4M120.9 84.2v4M126.3 80.1h4M141.2 154.6h4"/>
<path d="M152 154.6h4.1"/>
<circle cx="126.6" cy="63.7" r=".34"/>
</g>
<path d="M118 63.1h1.8" fill="none" stroke="#004080" stroke-width=".14"/>
<path d="M72.1 54.3v1.4M101.9 81.4h4.1M138.5 143.8h6.7" fill="none" stroke="#800040" stroke-width=".14"/>
<path d="M145.2 153.3h6.8v5.4h-6.8z" fill="none" stroke="#00f" stroke-width=".14"/>
<circle cx="144.8" cy="156" r=".34" fill="#fff"/>
<g fill="none" stroke="#f00" stroke-width=".14">
<path d="M141.2 156h3.2M141.2 157.4h4M152 157.4h4.1"/>
<circle cx="144.8" cy="156" r=".34"/>
</g>
<path d="M176.4 76v19" fill="none" stroke="#800040" stroke-width=".14"/>
<circle cx="176.4" cy="94.9" r=".21" fill="#f0f"/>
<circle cx="176.4" cy="94.9" r=".21" fill="none" stroke="#f0f" stroke-width=".14"/>
<path d="M42.9 71.9h1.4M43.6 71.9v1.4" fill="none" stroke="#f00" stroke-width=".14"/>
<path d="M188.6 51.6h2.7M158.8 78.7v36.6M183.2 76v1.3M191.3 67.9h10.9M162.9 90.9v39.4M148 119.4h28.4M148 112.6h8.1M148 120.8h16.2" fill="none" stroke="#800040" stroke-width=".14"/>
<path d="M191.1 51.4h.3v.3h-.3v-.2z" fill-rule="evenodd" fill="#f0f"/>
<path d="M191.1 51.4h.3v.3h-.3v-.2z" fill="none" stroke="#f0f" stroke-width=".14"/>
<circle cx="188.6" cy="51.5" r=".21" fill="#f0f"/>
<circle cx="188.6" cy="51.5" r=".21" fill="none" stroke="#f0f" stroke-width=".14"/>
<path d="M225.2 48.9v2.7M99.1 78.7h6.9M107.3 90.9v42.1M107.3 142.5v12.1M157.4 157.4v2.7M172.4 153.3v1.3" fill="none" stroke="#800040" stroke-width=".14"/>
<g fill="none" stroke="#f00" stroke-width=".14">
<path d="M158.8 52.4v.6M60.5 71.9h1.4M61.2 71.9v1.4M217.8 95h1.3M218.4 95v1.3M234.7 107.2h2.7M235.1 107.6h1.9M235.5 108h1.1M235.9 108.4h.3"/>
<circle cx="158.7" cy="51.9" r=".34"/>
</g>
<path d="M107.1 143.6h.3v.3h-.3z" fill-rule="evenodd" fill="#f0f"/>
<path d="M107.1 143.6h.3v.3h-.3z" fill="none" stroke="#f0f" stroke-width=".14"/>
<path d="M222.5 69.1h-.7v1.6h.7v-.1M222.5 67.9h5.4v4h-5.4zM227.9 69.2v-.1h.7v1.6h-.7M183.2 93.6h1.4v2.7h-1.4zM115.6 158.3h2.4M115.6 157.6h2.4M116.8 157.4v.2M116.8 158.3v.4" fill="none" stroke="#00f" stroke-width=".14"/>
<path d="M223.9 63.8v4.1M225.2 63.8v4.1M226.6 63.8v4.1M65.3 81.4h2.7M65.7 81.8h1.9M66.1 82.3h1.1M66.5 82.6h.3M179.2 95h4M106.6 141.1h1.4M107.3 141.1v1.4M116.8 156v1.4M116.8 158.7v1.4" fill="none" stroke="#f00" stroke-width=".14"/>
<path d="M234.7 58.4v4M99.1 78.7v39.3M191.3 61.1v6.8M101.9 81.4v33.9M107.3 90.9h9.5M112.7 89.6h2.7M234.7 99.1h1.4M164.2 120.8v23M156.1 154.6h6.8M172.4 154.6v1.4M135.8 161.5v4" fill="none" stroke="#800040" stroke-width=".14"/>
<circle cx="116.7" cy="90.8" r=".21" fill="#f0f"/>
<circle cx="116.7" cy="90.8" r=".21" fill="none" stroke="#f0f" stroke-width=".14"/>
<path d="M66.6 67.9v6.7M177.8 73.3v17.6M226.6 62.4h8.1M106 89.6h6.7M236.1 96.3v2.8M99.1 118h35.3M100.5 116.7h33.9M202.2 100.4v24.4M84.2 126.2h50.2M124.9 154.6h16.3" fill="none" stroke="#800040" stroke-width=".14"/>
<circle cx="177.7" cy="90.8" r=".21" fill="#f0f"/>
<circle cx="177.7" cy="90.8" r=".21" fill="none" stroke="#f0f" stroke-width=".14"/>
<path d="M177.9 55.2h2.4M177.9 54.6h2.4M179.2 54.3v.3M179.2 55.2v.5M65.4 77h2.5M65.4 76.3h2.5M66.6 76v.3M66.6 77v.3M110 154.6l.4 .5 .8-.8 .9 .8 .8-.8 .8 .8 .4-.5" fill="none" stroke="#00f" stroke-width=".14"/>
<g fill="none" stroke="#f00" stroke-width=".14">
<path d="M179.2 53v1.3M179.2 55.7v1.3M225.2 48.3v.6M66.6 74.6v1.4M66.6 77.3v1.4M118.2 127.5h1.3M118.2 126.9v1.3M108.7 154.6h1.3M114.1 154.6h1.3"/>
<circle cx="225.2" cy="47.9" r=".34"/>
</g>
<path d="M171 51.6h8.2M73.4 112.6h61M203.5 101.8v24.4M234.7 100.4h1.4M148 122.1h29.8M162.9 154.6v1.4" fill="none" stroke="#800040" stroke-width=".14"/>
<circle cx="179.1" cy="51.5" r=".21" fill="#f0f"/>
<circle cx="179.1" cy="51.5" r=".21" fill="none" stroke="#f0f" stroke-width=".14"/>
<g fill="none" stroke="#800040" stroke-width=".14">
<path d="M72.1 53v1.3M225.2 58.4v5.4M43.6 74.6h1.4M61.2 73.3v1.3M81.5 71.9v1.4M195.4 70.6v52.9M203.5 66.5v35.3M156.1 80.1v8.1M115.4 124.8h1.4M107.3 143.8h16.3M130.3 143.8h8.2M135.8 156v5.5"/>
<path d="M116.8 160.1v1.4"/>
</g>
<path d="M158.8 55.7l.4 .3-.8 .9 .8 .8-.8 .8 .8 .8-.4 .4M182 74.3h2.4M182 73.6h2.4M183.2 73.3v.3M183.2 74.3v.3M111.4 95h2.7a1.35 1.35 0 0 1-1.4 1.3 1.35 1.35 0 0 1-1.3-1.3zM111.4 94.7a1.38 1.38 0 0 1 1.4-1.1 1.38 1.38 0 0 1 1.3 1.2M111.4 94.7h2.7M124.9 143.8l.4 .4 .9-.8 .8 .8 .8-.8 .8 .8 .4-.4" fill="none" stroke="#00f" stroke-width=".14"/>
<path d="M158.8 54.3v1.4M158.8 59.7v1.4M183.2 71.9v1.4M183.2 74.6v1.4M89.7 81.4h2.7M90.1 81.8h1.9M90.5 82.3h1.1M90.9 82.6h.2M112.7 92.3v1.3M112.7 96.3v1.4M123.6 143.8h1.3M129 143.8h1.3" fill="none" stroke="#f00" stroke-width=".14"/>
<path d="M110 61.1h16.3v23.1h-16.3z" fill="none" stroke="#008080" stroke-width=".81"/>
<path d="M203.3 101.6h.3v.2h-.3z" fill-rule="evenodd" fill="#f0f"/>
<path d="M203.3 101.6h.3v.2h-.3z" fill="none" stroke="#f0f" stroke-width=".14"/>
<path d="M72.1 54.3h1.3M50.4 74.6h1.3M123.6 124.8h10.8" fill="none" stroke="#800040" stroke-width=".14"/>
<path d="M71.9 54.1l.1-.1 .1 .1v.3h-.2z" fill-rule="evenodd" fill="#f0f"/>
<path d="M71.9 54.1l.1-.1 .1 .1v.3h-.2z" fill="none" stroke="#f0f" stroke-width=".14"/>
<path d="M204.9 103.1v24.4" fill="none" stroke="#800040" stroke-width=".14"/>
<path d="M204.7 102.9h.3v.3h-.3z" fill-rule="evenodd" fill="#f0f"/>
<path d="M204.7 102.9h.3v.3h-.3z" fill="none" stroke="#f0f" stroke-width=".14"/>
<path d="M74.8 81.4h2.7M75.2 81.8h1.8M75.6 82.3h1.1M76 82.6h.2M130.3 135.7h2.8M130.7 136.1h1.9M131.1 136.5h1.1M131.6 136.9h.2M162.9 156v1.4M162.9 158.7v1.4" fill="none" stroke="#f00" stroke-width=".14"/>
<path d="M161.5 157.4h2.7M162.9 157.9a2.19 2.19 0 0 1 1.3 .5M162.9 157.9a2.16 2.16 0 0 0-1.4 .5M162.9 157.9v.8" fill="none" stroke="#00f" stroke-width=".14"/>
<path d="M169.6 77.3v40.7h-21.6M148 124.8h54.2" fill="none" stroke="#800040" stroke-width=".14"/>
<use href="#words"/>
</svg>
